VERSION 5.7 ;
  NOWIREEXTENSIONATPIN ON ;
  DIVIDERCHAR "/" ;
  BUSBITCHARS "[]" ;
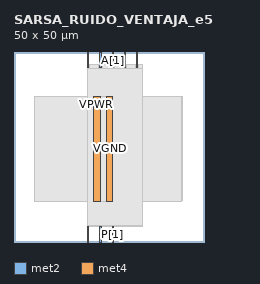
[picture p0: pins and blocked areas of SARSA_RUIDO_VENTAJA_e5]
MACRO SARSA_RUIDO_VENTAJA_e5
  CLASS BLOCK ;
  FOREIGN SARSA_RUIDO_VENTAJA_e5 ;
  ORIGIN 0.000 0.000 ;
  SIZE 50.000 BY 50.000 ;
  PIN A[0]
    DIRECTION INPUT ;
    USE SIGNAL ;
    ANTENNAGATEAREA 0.196500 ;
    PORT
      LAYER met2 ;
        RECT 32.290 46.000 32.570 50.000 ;
    END
  END A[0]
  PIN A[1]
    DIRECTION INPUT ;
    USE SIGNAL ;
    ANTENNAGATEAREA 0.196500 ;
    PORT
      LAYER met2 ;
        RECT 25.850 46.000 26.130 50.000 ;
    END
  END A[1]
  PIN B[0]
    DIRECTION INPUT ;
    USE SIGNAL ;
    ANTENNAGATEAREA 0.196500 ;
    PORT
      LAYER met2 ;
        RECT 19.410 0.000 19.690 4.000 ;
    END
  END B[0]
  PIN B[1]
    DIRECTION INPUT ;
    USE SIGNAL ;
    ANTENNAGATEAREA 0.196500 ;
    PORT
      LAYER met2 ;
        RECT 19.410 46.000 19.690 50.000 ;
    END
  END B[1]
  PIN P[0]
    DIRECTION OUTPUT ;
    USE SIGNAL ;
    ANTENNADIFFAREA 0.445500 ;
    PORT
      LAYER met2 ;
        RECT 22.630 46.000 22.910 50.000 ;
    END
  END P[0]
  PIN P[1]
    DIRECTION OUTPUT ;
    USE SIGNAL ;
    ANTENNADIFFAREA 0.445500 ;
    PORT
      LAYER met2 ;
        RECT 25.850 0.000 26.130 4.000 ;
    END
  END P[1]
  PIN P[2]
    DIRECTION OUTPUT ;
    USE SIGNAL ;
    ANTENNADIFFAREA 0.445500 ;
    PORT
      LAYER met2 ;
        RECT 22.630 0.000 22.910 4.000 ;
    END
  END P[2]
  PIN P[3]
    DIRECTION OUTPUT ;
    USE SIGNAL ;
    ANTENNADIFFAREA 0.445500 ;
    PORT
      LAYER met2 ;
        RECT 29.070 46.000 29.350 50.000 ;
    END
  END P[3]
  PIN VGND
    DIRECTION INOUT ;
    USE GROUND ;
    PORT
      LAYER met4 ;
        RECT 24.340 10.640 25.940 38.320 ;
    END
  END VGND
  PIN VPWR
    DIRECTION INOUT ;
    USE POWER ;
    PORT
      LAYER met4 ;
        RECT 21.040 10.640 22.640 38.320 ;
    END
  END VPWR
  OBS
      LAYER nwell ;
        RECT 5.330 10.795 44.350 38.165 ;
      LAYER li1 ;
        RECT 5.520 10.795 44.160 38.165 ;
      LAYER met1 ;
        RECT 5.520 10.640 44.160 38.320 ;
      LAYER met2 ;
        RECT 19.970 45.720 22.350 46.650 ;
        RECT 23.190 45.720 25.570 46.650 ;
        RECT 26.410 45.720 28.790 46.650 ;
        RECT 29.630 45.720 32.010 46.650 ;
        RECT 32.850 45.720 33.940 46.650 ;
        RECT 19.420 4.280 33.940 45.720 ;
        RECT 19.970 4.000 22.350 4.280 ;
        RECT 23.190 4.000 25.570 4.280 ;
        RECT 26.410 4.000 33.940 4.280 ;
      LAYER met3 ;
        RECT 21.050 10.715 25.930 38.245 ;
  END
END SARSA_RUIDO_VENTAJA_e5
END LIBRARY

